One B-rep face of a CAD part: STEP entity #407.
In plain terms, the planar face has unit normal (1, 0, 0).
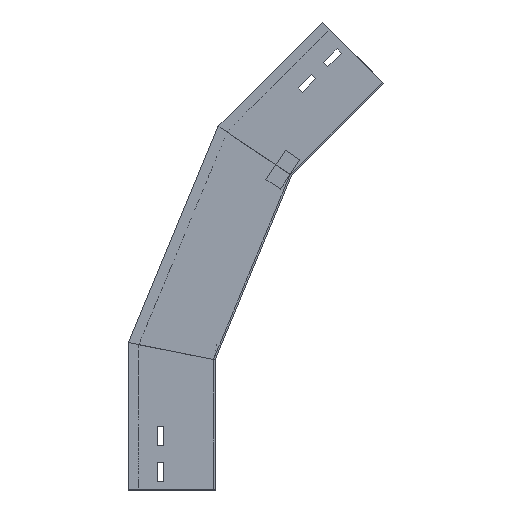
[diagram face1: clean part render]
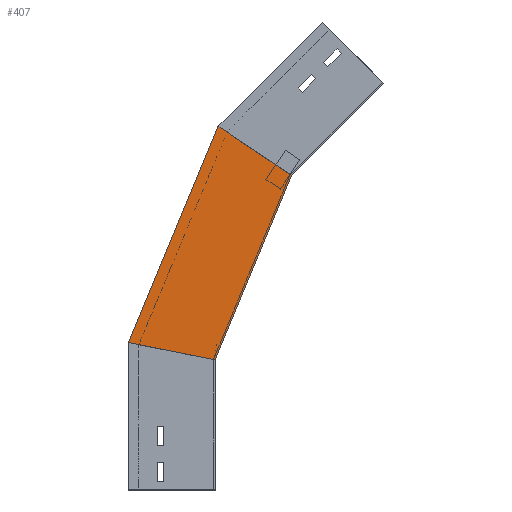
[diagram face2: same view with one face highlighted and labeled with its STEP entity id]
Its self-contained STEP definition (entity closure, numbers rounded to 3 decimals):
#7 = VECTOR ( 'NONE', #789, 1000. ) ;
#15 = EDGE_CURVE ( 'NONE', #1278, #110, #1059, .T. ) ;
#20 = FACE_OUTER_BOUND ( 'NONE', #692, .T. ) ;
#27 = DIRECTION ( 'NONE',  ( 0., -0.383, 0.924 ) ) ;
#110 = VERTEX_POINT ( 'NONE', #822 ) ;
#127 = DIRECTION ( 'NONE',  ( 0., 0., -1. ) ) ;
#168 = VECTOR ( 'NONE', #817, 1000. ) ;
#259 = EDGE_CURVE ( 'NONE', #618, #1278, #307, .T. ) ;
#270 = LINE ( 'NONE', #1078, #777 ) ;
#307 = LINE ( 'NONE', #1133, #7 ) ;
#407 = ADVANCED_FACE ( 'NONE', ( #20 ), #1281, .T. ) ;
#428 = CARTESIAN_POINT ( 'NONE',  ( 0., 100., 169.891 ) ) ;
#493 = LINE ( 'NONE', #963, #1485 ) ;
#551 = ORIENTED_EDGE ( 'NONE', *, *, #894, .T. ) ;
#618 = VERTEX_POINT ( 'NONE', #428 ) ;
#692 = EDGE_LOOP ( 'NONE', ( #551, #1282, #968, #759 ) ) ;
#705 = CARTESIAN_POINT ( 'NONE',  ( 0., 8.412, 129.693 ) ) ;
#759 = ORIENTED_EDGE ( 'NONE', *, *, #259, .F. ) ;
#777 = VECTOR ( 'NONE', #1088, 1000. ) ;
#789 = DIRECTION ( 'NONE',  ( 0., -0.981, -0.195 ) ) ;
#817 = DIRECTION ( 'NONE',  ( 0., -0.383, 0.924 ) ) ;
#821 = CARTESIAN_POINT ( 'NONE',  ( 0., 8.412, 129.693 ) ) ;
#822 = CARTESIAN_POINT ( 'NONE',  ( 0., -88.017, 362.492 ) ) ;
#892 = EDGE_CURVE ( 'NONE', #1205, #110, #270, .T. ) ;
#894 = EDGE_CURVE ( 'NONE', #618, #1205, #493, .T. ) ;
#963 = CARTESIAN_POINT ( 'NONE',  ( 0., 100.799, 167.961 ) ) ;
#965 = AXIS2_PLACEMENT_3D ( 'NONE', #705, #1169, #127 ) ;
#968 = ORIENTED_EDGE ( 'NONE', *, *, #15, .F. ) ;
#1059 = LINE ( 'NONE', #821, #168 ) ;
#1078 = CARTESIAN_POINT ( 'NONE',  ( 0., -128.891, 335.181 ) ) ;
#1088 = DIRECTION ( 'NONE',  ( 0., -0.831, -0.556 ) ) ;
#1133 = CARTESIAN_POINT ( 'NONE',  ( 0., -28.701, 144.291 ) ) ;
#1169 = DIRECTION ( 'NONE',  ( 1., 0., 0. ) ) ;
#1205 = VERTEX_POINT ( 'NONE', #1234 ) ;
#1234 = CARTESIAN_POINT ( 'NONE',  ( 0., -3.241, 419.138 ) ) ;
#1278 = VERTEX_POINT ( 'NONE', #1295 ) ;
#1281 = PLANE ( 'NONE',  #965 ) ;
#1282 = ORIENTED_EDGE ( 'NONE', *, *, #892, .T. ) ;
#1295 = CARTESIAN_POINT ( 'NONE',  ( 0., 0., 150. ) ) ;
#1485 = VECTOR ( 'NONE', #27, 1000. ) ;
